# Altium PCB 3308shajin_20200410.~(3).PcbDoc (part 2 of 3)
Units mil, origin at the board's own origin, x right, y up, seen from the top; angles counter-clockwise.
Board outline 4724.41 x 2952.76 mil, 4 copper layers (Top, GND, Power, Bottom), stack 35.4 mil thick; 266 components, 266 nets, 1212 pads, 1516 vias.
Unrouted connection lines stored in the file: 149.

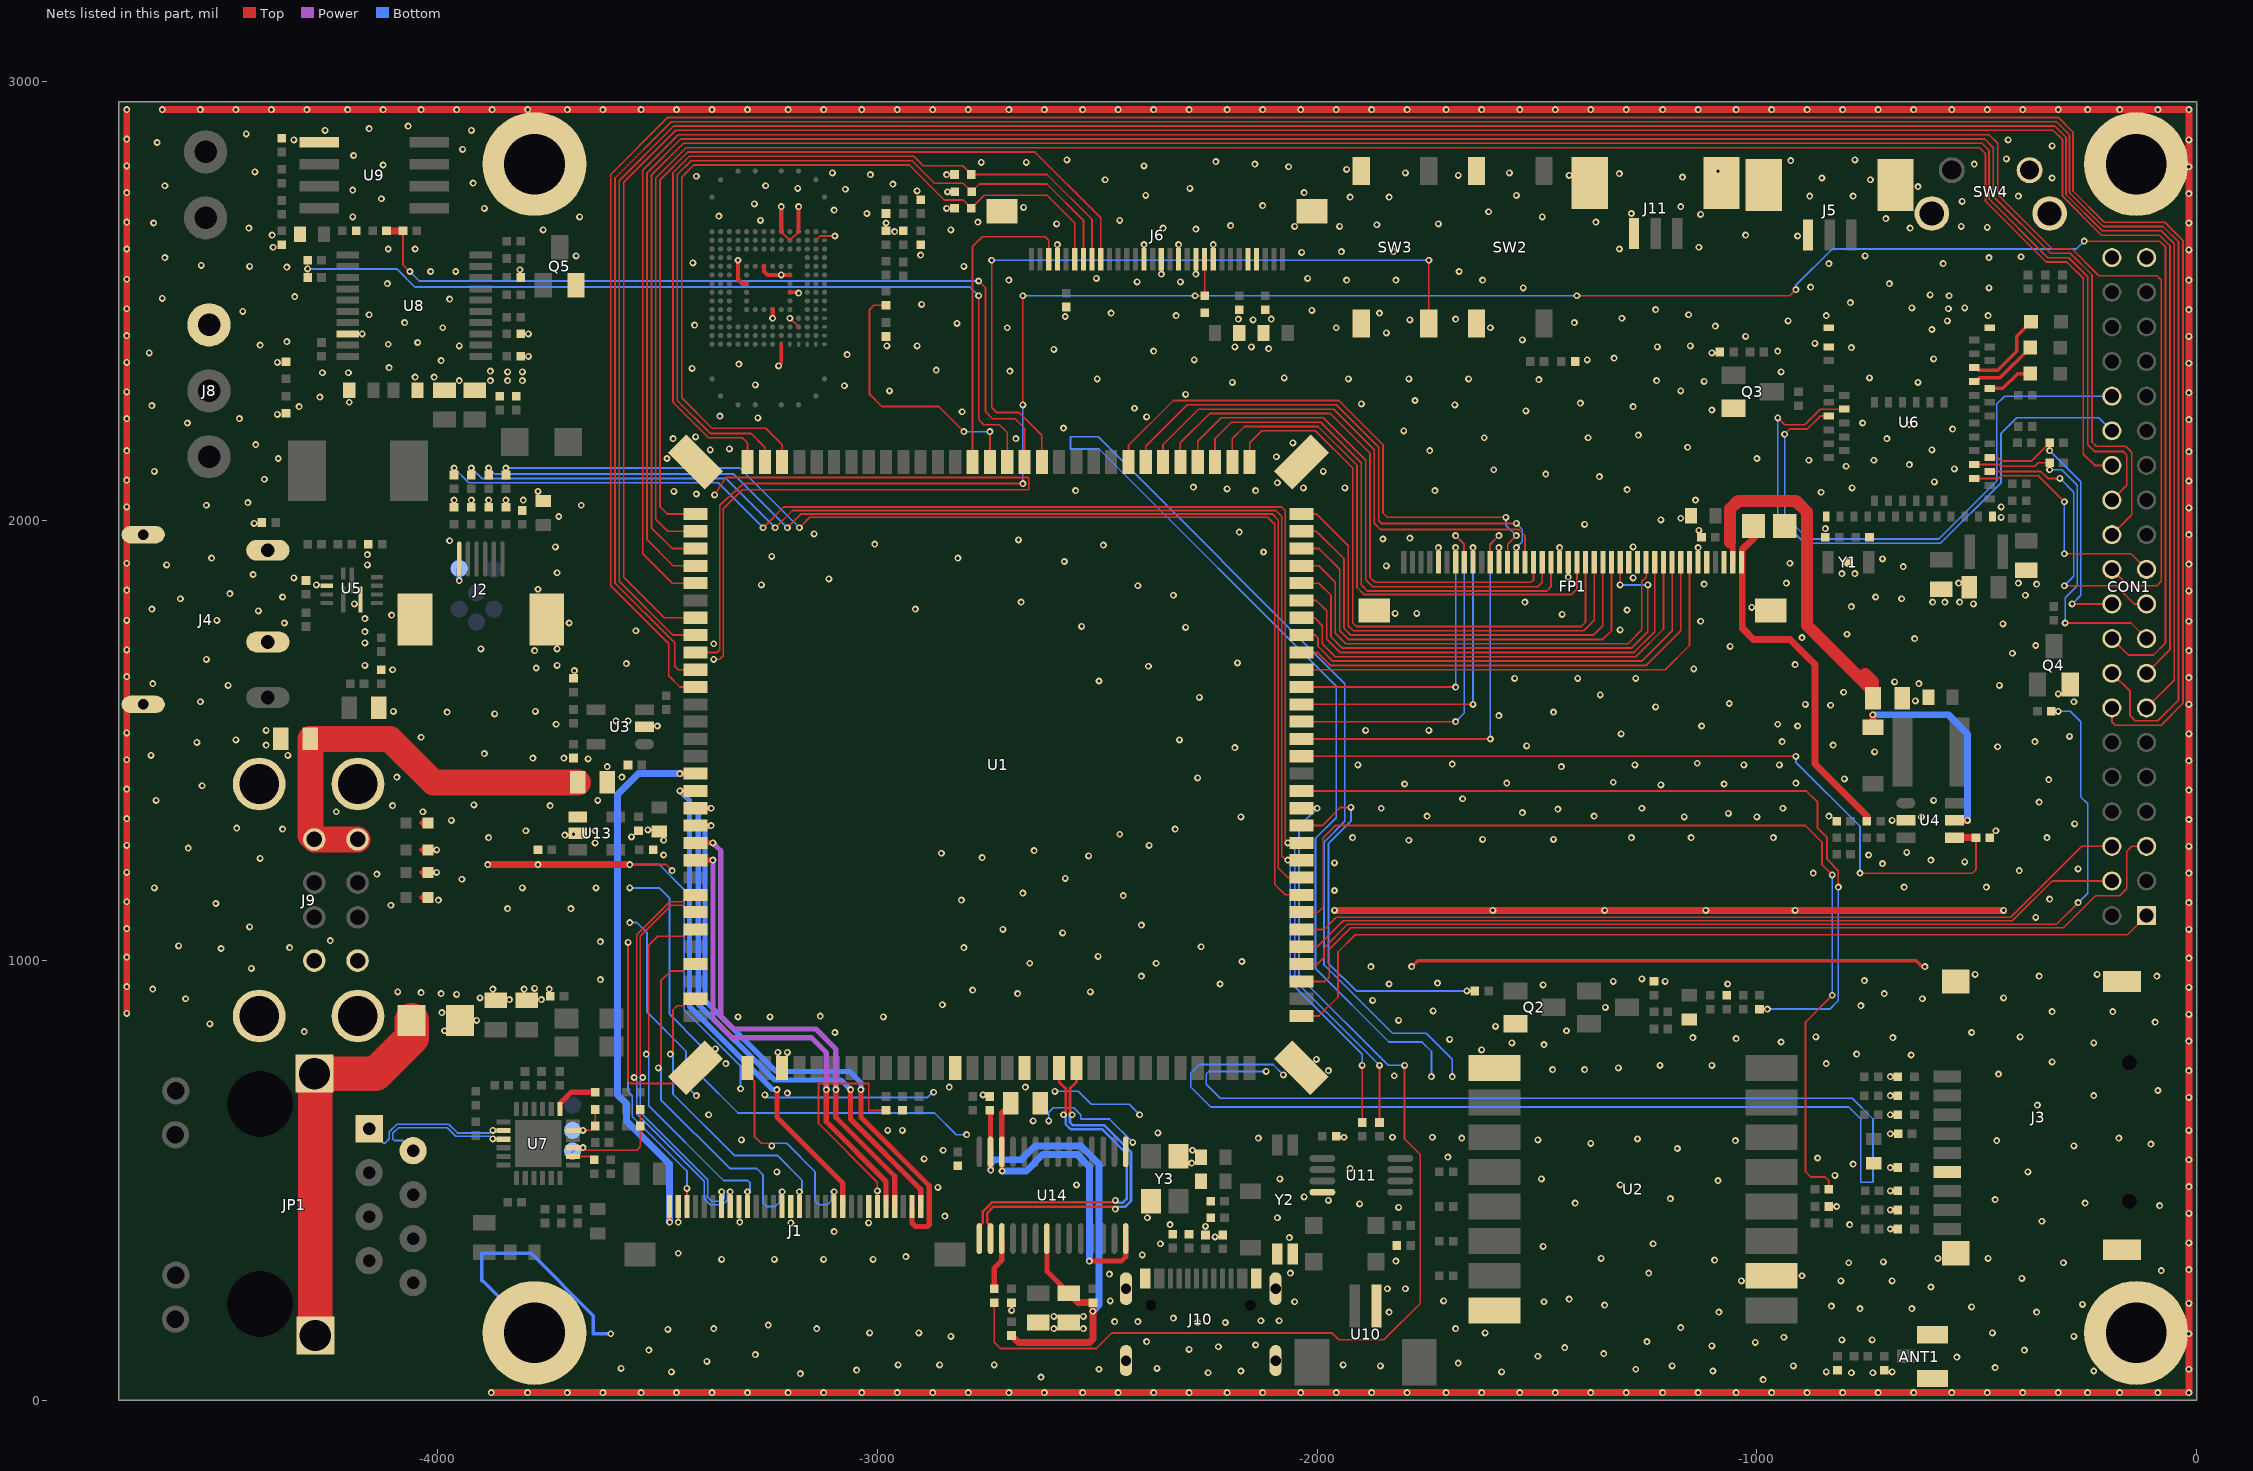
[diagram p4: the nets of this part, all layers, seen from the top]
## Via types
v1: diameter 15.75, hole 7.87, Top to Bottom, 1478 vias
v2: diameter 19.68, hole 11.81, Top to Bottom, 38 vias

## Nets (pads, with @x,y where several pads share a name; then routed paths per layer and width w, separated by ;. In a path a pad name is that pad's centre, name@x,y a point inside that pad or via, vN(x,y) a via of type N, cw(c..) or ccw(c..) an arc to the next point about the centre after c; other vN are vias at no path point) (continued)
FLASH_ALE/EMMC_RST: R77.1 U1.46 | length 612
  Top w3.94: R77.1@-2980.31,2490.16 -3007.87,2490.16 -3017.72,2480.31 -3017.72,2287.4 -2990.16,2259.84 -2860.24,2259.84 v1(-2803.15,2202.76) ; U1.46@-2744.09,2133.86 v1(-2744.09,2202.76)
  Bottom w3.94: v1(-2803.15,2202.76) v1(-2744.09,2202.76)
FLASH_CS0N: R64.2 R66.2 U1.44 | length 1923.3
  Top w3.94: R66.2@-4078.74,2659.45 -4078.74,2582.68 v1(-4062.99,2566.93) ; v1(-2769.69,2545.28) -2753.94,2529.53 -2753.94,2248.03 -2738.19,2232.28 -2687.01,2232.28 -2665.35,2210.63 U1.44@-2665.35,2133.86
  Top w15.75: R64.2@-4116.14,2659.45 R66.2@-4078.74,2659.45
  Bottom w3.94: v1(-4062.99,2566.93) -4041.34,2545.28 v1(-2769.69,2545.28)
FLASH_RDN: J6.28 U1.47 | length 718.9
  Top w3.94: U1.47@-2783.46,2133.86 -2783.46,2624.02 -2761.81,2645.67 -2618.11,2645.67 -2610.24,2637.8 J6.28@-2610.24,2594.49
FLASH_RDY: R63.2 R65.2 U1.45 | length 2015.9
  Top w3.94: R63.2@-4295.28,2553.15 v1(-4295.28,2572.83) R65.2@-4295.28,2592.52 ; v1(-2769.69,2511.81) -2769.69,2230.31 -2757.87,2218.5 -2722.44,2218.5 -2704.72,2200.79 U1.45@-2704.72,2133.86
  Bottom w3.94: v1(-4295.28,2572.83) -4092.52,2572.83 -4051.18,2531.5 -2789.37,2531.5 v1(-2769.69,2511.81)
GBE0_SDP: R81.2 U14.17 | length 121.2
  Top w11.81: R81.2@-2734.25,253.94 -2734.25,301.18 -2717.03,318.4 U14.17@-2717.03,368.03
GND: ANT1.2 ANT1.3 C1.2 C2.2 C3.2 C4.2 C5.2 C7.2 C8.2 C9.2 C10.2 C11.2 C12.2 C13.2 C14.2 C15.1 C16.2 C17.2 C19.2 C20.2 C21.2 C22.2 C23.2 C24.2 C25.2 C26.2 C27.2 C28.2 C29.2 C30.2 C31.2 C32.1 C33.1 C34.1 C49.2 C50.2 C51.2 C52.2 C53.2 C54.2 C55.2 C58.2 C59.2 C60.1 C61.1 C62.1 C63.2 C64.1 C65.2 C66.2 C67.2 C68.2 C69.2 C70.1 C71.1 C72.2 C73.2 C74.2 C75.2 C76.2 C77.1 C78.1 C79.1 C80.1 CD1.1 CD2.1 CD3.1 CON1.39 CON1.40 D2.2 D3.2 D4.2 D5.2 D6.2 D7.2 D8.2 D9.2 D10.2 D11.2 D12.2 D16.2 D17.2 E1.2 E2.2 ED1.2 ED2.1 ED3.2 ED4.1 ED5.2 ED6.2 ED7.2 ED8.2 ED9.2 ED10.2 FP1.3 FP1.5 FP1.6 FP1.13 FP1.14 FP1.21 FP1.22 FP1.29 FP1.36 FP1.41 FP1.42 J1.2 J1.3 J1.9 J1.15 J1.24 J1.25 J2.1 J2.7 J2.8 J3.6 J3.10 J3.11 J3.12 J3.13 J4.2 J4.3 J4.4 J4.5 J5.3 J5.4 J5.5 J6.4 J6.5 J6.9 J6.11 J6.13 J6.15 J6.17 J6.27 J6.31 J6.32 J8.3 J9.4 J9.8 J9.9 J9.10 J9.11 J9.12 J10.A1 J10.A12 J10.B1 J10.B12 J10.E1 J10.E2 J10.E3 J10.E4 J11.3 J11.4 J11.5 P1.1 Q2.2 Q3.2 Q4.2 Q5.2 R3.2 R16.1 R20.2 R30.1 R35.1 R41.2 R57.1 R62.2 R71.2 R73.2 R82.1 R83.1 R84.1 R85.1 R87.1 SW2.1 SW2.4 SW3.1 SW3.4 SW4.1 SW4.3 SW4.4 TP1.1 TP2.1 TP3.1 TP4.1 U1.93 U1.103 U1.107 U1.121 U1.122 U1.123 U1.124 U2.2 U2.9 U2.16 U3.2 U4.2 U5.2 U5.10 U6.1 U6.2 U6.15 U6.33 U6.55 U8.18 U9.5 U10.1 U11.4 U13.2 U14.1 Y1.3 Y2.3 Y2.4 Y3.2 Y3.4 | length 32052.8
  Top w3.94: v1(-3566.93,1041.34) -3566.93,726.38 -3561.02,720.47 -3452.76,720.47 -3416.93,756.3 U1.124@-3413.78,756.3 ; v1(-3562.99,1218.5) -3480.31,1218.5 v1(-3466.54,1204.72) ; J1.3@-3433.07,440.94 v1(-3433.07,482.28) ; v1(-3372.05,1685.04) -3358.27,1685.04 -3350.39,1692.91 -3350.39,2027.56 -3307.09,2070.87 -2655.51,2070.87 -2655.51,2098.43 -3344.49,2098.43 v1(-3370.08,2059.06) ; -3218.5,2657.48 -3198.82,2637.8 -3179.13,2657.48 ; v1(-3198.82,2460.63) -3179.13,2440.94 ; -3139.76,2637.8 -3129.92,2647.64 v1(-3096.46,2647.64) ; v1(-3000,476.38) -3000,496.06 -3133.86,629.92 -3133.86,720.47 -3019.69,720.47 -3019.69,657.48 -3017.72,659.45 R3.2@-2980.31,659.45
  Top w7.87: v1(-3224.41,2352.36) -3218.5,2358.27 -3218.5,2401.57 ; -3198.82,2519.68 -3181.1,2519.68 v1(-3179.13,2517.72) ; v1(-1785.43,986.22) -1771.65,1000 -637.8,1000 -624.02,986.22 v1(-618.11,986.22)
  Top w9.84: v1(-3316.93,2592.52) -3316.93,2549.21 -3307.09,2539.37 -3297.24,2539.37 ; -3257.87,2578.74 -3257.87,2566.93 -3250,2559.06 v1(-3218.5,2559.06) -3198.82,2559.06 ; v1(-3238.19,2460.63) -3238.19,2480.31 ; -3218.5,2657.48 v1(-3218.5,2714.57) ; -3179.13,2657.48 v1(-3179.13,2714.57)
  Top w15.75: v1(-4706.69,879.92) v1(-4706.69,940.94) v1(-4706.69,1007.87) v1(-4706.69,1072.83) v1(-4706.69,1133.86) v1(-4706.69,1200.79) v1(-4706.69,1261.81) v1(-4706.69,1322.83) v1(-4706.69,1389.76) v1(-4706.69,1456.69) v1(-4706.69,1517.72) v1(-4706.69,1645.67) v1(-4706.69,1706.69) v1(-4706.69,1773.62) v1(-4706.69,1842.52) v1(-4706.69,1903.54) v1(-4706.69,2031.5) v1(-4706.69,2092.52) v1(-4706.69,2159.45) v1(-4706.69,2232.28) v1(-4706.69,2293.31) v1(-4706.69,2360.24) v1(-4706.69,2421.26) v1(-4706.69,2482.28) v1(-4706.69,2549.21) v1(-4706.69,2618.11) v1(-4706.69,2679.13) v1(-4706.69,2746.06) v1(-4706.69,2807.09) v1(-4706.69,2868.11) v1(-4706.69,2935.04) ; v1(-4625.98,2935.04) v1(-4539.37,2935.04) v1(-4458.66,2935.04) v1(-4377.95,2935.04) v1(-4297.24,2935.04) v1(-4204.72,2935.04) v1(-4124.02,2935.04) v1(-4037.4,2935.04) v1(-3956.69,2935.04) v1(-3875.98,2935.04) v1(-3795.28,2935.04) v1(-3704.72,2935.04) v1(-3624.02,2935.04) v1(-3537.4,2935.04) v1(-3456.69,2935.04) v1(-3375.98,2935.04) v1(-3295.28,2935.04) v1(-3202.76,2935.04) v1(-3122.05,2935.04) v1(-3035.43,2935.04) v1(-2954.72,2935.04) v1(-2874.02,2935.04) v1(-2793.31,2935.04) v1(-2700.79,2935.04) v1(-2620.08,2935.04) v1(-2533.46,2935.04) v1(-2452.76,2935.04) v1(-2372.05,2935.04) v1(-2291.34,2935.04) v1(-2204.72,2935.04) v1(-2124.02,2935.04) v1(-2037.4,2935.04) v1(-1956.69,2935.04) v1(-1875.98,2935.04) v1(-1795.28,2935.04) v1(-1706.69,2935.04) v1(-1625.98,2935.04) v1(-1539.37,2935.04) v1(-1458.66,2935.04) v1(-1377.95,2935.04) v1(-1297.24,2935.04) v1(-1214.57,2935.04) v1(-1133.86,2935.04) v1(-1047.24,2935.04) v1(-966.54,2935.04) v1(-885.83,2935.04) v1(-805.12,2935.04) v1(-724.41,2935.04) v1(-643.7,2935.04) v1(-557.09,2935.04) v1(-476.38,2935.04) v1(-395.67,2935.04) v1(-314.96,2935.04) v1(-248.03,2935.04) v1(-175.2,2935.04) v1(-88.58,2935.04) v1(-17.72,2935.04) v1(-17.72,2866.14) v1(-17.72,2805.12) v1(-17.72,2744.09) v1(-17.72,2677.17) v1(-17.72,2616.14) v1(-17.72,2547.24) v1(-17.72,2480.31) v1(-17.72,2419.29) v1(-17.72,2358.27) v1(-17.72,2291.34) v1(-17.72,2230.31) v1(-17.72,2157.48) v1(-17.72,2090.55) v1(-17.72,2029.53) v1(-17.72,1968.5) v1(-17.72,1901.57) v1(-17.72,1840.55) v1(-17.72,1771.65) v1(-17.72,1704.72) v1(-17.72,1643.7) v1(-17.72,1582.68) v1(-17.72,1515.75) v1(-17.72,1454.72) v1(-17.72,1387.8) v1(-17.72,1320.87) v1(-17.72,1259.84) v1(-17.72,1198.82) v1(-17.72,1131.89) v1(-17.72,1070.87) v1(-17.72,1005.91) v1(-17.72,938.98) v1(-17.72,877.95) v1(-17.72,816.93) v1(-17.72,750) v1(-17.72,688.98) v1(-17.72,614.17) v1(-17.72,547.24) v1(-17.72,486.22) v1(-17.72,425.2) v1(-17.72,358.27) v1(-17.72,297.24) v1(-17.72,220.47) v1(-17.72,151.57) v1(-17.72,70.87) v1(-17.72,17.72) v1(-88.58,17.72) v1(-175.2,17.72) v1(-248.03,17.72) v1(-314.96,17.72) v1(-395.67,17.72) v1(-476.38,17.72) v1(-557.09,17.72) v1(-643.7,17.72) v1(-724.41,17.72) v1(-805.12,17.72) v1(-885.83,17.72) v1(-966.54,17.72) v1(-1047.24,17.72) v1(-1133.86,17.72) v1(-1214.57,17.72) v1(-1297.24,17.72) v1(-1377.95,17.72) v1(-1458.66,17.72) v1(-1539.37,17.72) v1(-1625.98,17.72) v1(-1706.69,17.72) v1(-1795.28,17.72) v1(-1875.98,17.72) v1(-1956.69,17.72) v1(-2037.4,17.72) v1(-2124.02,17.72) v1(-2204.72,17.72) v1(-2291.34,17.72) v1(-2372.05,17.72) v1(-2452.76,17.72) v1(-2533.46,17.72) v1(-2620.08,17.72) v1(-2700.79,17.72) v1(-2793.31,17.72) v1(-2874.02,17.72) v1(-2954.72,17.72) v1(-3035.43,17.72) v1(-3122.05,17.72) v1(-3202.76,17.72) v1(-3295.28,17.72) v1(-3375.98,17.72) v1(-3456.69,17.72) v1(-3537.4,17.72) v1(-3624.02,17.72) v1(-3704.72,17.72) v1(-3795.28,17.72) v1(-3877.95,17.72) ; v1(-3885.83,1218.5) v1(-3771.65,1218.5) v1(-3562.99,1218.5) ; v1(-1960.63,1114.17) v1(-1600.39,1114.17) v1(-1346.46,1114.17) v1(-1116.14,1114.17) v1(-913.39,1114.17) v1(-438.98,1114.17)
  Bottom w3.94: v1(-3566.93,1041.34) -3566.93,702.76 -3557.09,692.91 -3557.09,645.67 -3433.07,521.65 v1(-3433.07,482.28) ; v1(-3562.99,1086.61) -3547.24,1086.61 -3523.62,1062.99 -3523.62,882.35 -3435.04,793.76 -3435.04,716.54 v1(-3411.42,692.91) ; v1(-3562.99,1165.35) -3496.06,1165.35 -3472.44,1141.73 -3472.44,877.95 -3403.54,809.06 -3403.54,740.16 -3316.93,653.54 -2870.08,653.54 -2820.87,604.33 v1(-2797.24,604.33) ; v1(-3562.99,1218.5) -3496.06,1218.5 -3438.98,1161.42 -3438.98,887.8 -3311.02,759.84 v1(-3311.02,708.66) ; v1(-3255.91,694.88) -3250,688.98 -2885.83,688.98 -2875.98,698.82 -2874.02,698.82 v1(-2872.05,700.79) ; v1(-2610.24,635.83) -2610.24,655.51 -2600.39,665.35 -2553.15,665.35 -2537.4,649.61 -2537.4,639.76 -2472.44,639.76 v1(-2419.29,586.61) ; v1(-2596.46,702.76) -2543.31,702.76 -2513.78,673.23 -2427.17,673.23 v1(-2403.54,649.61) ; v1(-2116.14,748.03) -2246.06,748.03 -2251.97,742.13 -2251.97,718.5 -2220.47,687.01 -783.46,687.01 -736.22,639.76 -736.22,496.06 -763.78,496.06 -763.78,639.76 -791.34,667.32 -2242.13,667.32 -2287.4,712.6 -2287.4,744.09 -2267.72,763.78 -2100.39,763.78 v1(-2076.77,740.16) ; v1(-1740.16,736.22) -1740.16,793.31 -1761.81,814.96 -1836.61,814.96 -2003.94,982.28 -2003.94,1277.56 -1956.69,1324.8 -1956.69,1624.02 -2496.06,2163.39 -2561.02,2163.39 -2561.02,2190.94 -2498.03,2190.94 -1937.01,1629.92 -1937.01,1316.93 -1984.25,1269.68 -1984.25,990.16 -1828.74,834.65 -1751.97,834.65 -1692.91,775.59 v1(-1692.91,736.22)
  Bottom w7.87: TP1.1@-3779.53,153.54 -3897.64,271.65 -3899.61,271.65 -3899.61,334.65 -3787.4,334.65 -3645.67,192.91 -3645.67,151.57 v1(-3606.3,151.57)
  Bottom w11.81: v1(-3950.79,1864.17) P1.1@-3950.79,1891.73
  other v1: -986.22,47.24 -2627.95,53.15 -3175.2,61.02 -2248.03,62.99 -785.43,62.99 -736.22,62.99 -3468.5,64.96 -1580.71,64.96 -842.52,64.96 -692.91,64.96 -2173.23,66.93 -1100.39,66.93 -234.25,66.93 -3047.24,68.9 -2496.06,70.87 -1275.59,70.87 -3582.68,72.83 -2364.17,72.83 -458.66,74.8 -1856.3,78.74 -1192.91,78.74 -917.32,78.74 -2952.76,80.71 -2858.27,80.71 -2734.25,80.71 -1940.94,80.71 -1679.13,84.65 -3387.8,88.58 -545.28,98.43 -1498.03,100.39 -3277.56,104.33 -1348.43,106.3 -3519.69,114.17 -391.73,114.17 -2291.34,116.14 -1437.01,120.08 -2224.41,122.05 -1102.36,124.02 -2139.76,125.98 -1003.94,131.89 -2387.8,133.86 -1250,133.86 -807.09,137.8 -738.19,137.8 -938.98,143.7 -2832.68,145.67 -279.53,145.67 -3017.72,153.54 -2905.51,153.54 -1618.11,153.54 -464.57,153.54 -3476.38,161.42 -3372.05,163.39 -3137.8,163.39 -2598.43,163.39 -2531.5,163.39 -1685.04,163.39 -1173.23,165.35 -3248.03,171.26 -2271.65,177.17 -2208.66,177.17 -2460.63,179.13 -2407.48,179.13 -2127.95,181.1 -2086.61,181.1 -2326.77,187.01 -2598.43,190.94 -2531.5,190.94 -1836.61,200.79 -1086.61,200.79 -364.17,200.79 -2694.88,204.72 -765.75,208.66 -647.64,208.66 -511.81,212.6 -830.71,214.57 -1346.46,216.54 -259.84,218.5 -2051.18,224.41 -1484.25,224.41 -2470.47,226.38 -1712.6,226.38 -1427.17,230.31 -1840.55,253.94 -1799.21,253.94 -604.33,257.87 -1035.43,271.65 -809.06,271.65 -692.91,271.65 -397.64,277.56 -897.64,283.46 -2472.44,287.4 -2061.02,289.37 -1246.06,289.37 -80.71,295.28 -791.34,312.99 -303.15,312.99 -712.6,314.96 -1820.87,316.93 -1096.46,318.9 -3354.33,320.87 -3234.25,320.87 -3122.05,320.87 -3009.84,320.87 -1354.33,322.83 -588.58,322.83 -474.41,322.83 -2935.04,326.77 -2397.64,330.71 -3452.76,334.65 -1486.22,350.39 -2356.3,356.3 -1236.22,356.3 -2062.99,370.08 -2232.28,372.05 -3098.43,383.86 -696.85,389.76 -2253.94,395.67 -2334.65,399.61 -789.37,399.61 -3196.85,403.54 -3019.69,403.54 -3452.76,405.51 -3312.99,405.51 -352.36,407.48 -2385.83,415.35 -2090.55,415.35 -2846.46,419.29 -696.85,433.07 -1814.96,438.98 -818.9,440.94 -84.65,442.91 -1903.54,446.85 -1413.39,448.82 -253.94,448.82 -1974.41,454.72 -458.66,456.69 -1196.85,458.66 -2029.53,462.6 -696.85,476.38 -2862.2,484.25 -2547.24,490.16 -1311.02,490.16 -1088.58,500 -2084.65,503.94 -1490.16,503.94 -822.83,511.81 -3228.35,519.68 -383.86,519.68 -1925.2,527.56 -696.85,529.53 -781.5,537.4 -2285.43,539.37 -2893.7,549.21 -862.2,551.18 -1702.76,553.15 -2850.39,568.9 -2283.46,568.9 -1181.1,572.83 -279.53,578.74 -104.33,582.68 -1377.95,584.65 -1049.21,590.55 -454.72,590.55 -3309.06,592.52 -1498.03,592.52 -1271.65,594.49 -2133.86,596.46 -1671.26,596.46 -177.17,596.46 -1938.98,598.43 -1828.74,598.43 -1738.19,598.43 -696.85,606.3 -2362.2,608.27 -2976.38,614.17 -2942.91,614.17 -2645.67,635.83 -3383.86,649.61 -696.85,649.61 -362.2,671.26 -696.85,692.91 -234.25,692.91 -2759.84,694.88 -3204.72,698.82 -88.58,704.72 -2836.61,712.6 -2663.39,712.6 -696.85,736.22 -1824.8,738.19 -450.79,742.13 -1974.41,750 -1464.57,751.97 -1391.73,751.97 -1314.96,755.91 -1220.47,761.81 -1102.36,761.81 -3344.49,765.75 -842.52,765.75 -328.74,769.68 -2001.97,775.59 -649.61,785.43 -773.62,787.4 -3226.38,791.34 -3204.72,791.34 -1625.98,797.24 -3368.11,799.21 -1484.25,809.06 -1557.09,812.99 -234.25,812.99 -944.88,814.96 -1698.82,820.87 -1047.24,822.83 -1145.67,824.8 -690.94,824.8 -866.14,826.77 -401.57,826.77 -3096.46,836.61 -511.81,836.61 -4303.15,838.58 -3984.25,840.55 -1433.07,840.55 -1594.49,850.39 -4517.72,856.3 -94.49,860.24 -3911.42,864.17 -1814.96,864.17 -3316.93,872.05 -3244.09,872.05 -2986.22,872.05 -3129.92,874.02 -3990.16,881.89 -328.74,883.86 -190.94,883.86 -1736.22,885.83 -1344.49,893.7 -763.78,897.64 -2852.36,899.61 -1874.02,909.45 -3836.61,911.42 -3763.78,911.42 -4572.83,913.39 -624.02,913.39 -3903.54,915.35 -438.98,915.35 -3956.69,923.23 -3992.13,925.2 -2681.1,925.2 -710.63,925.2 -4037.4,927.17 -4090.55,929.13 -2515.75,929.13 -2783.46,933.07 -4647.64,935.04 -3874.02,935.04 -3803.15,935.04 -3746.06,935.04 -3779.53,937.01 -1486.22,944.88 -2220.47,946.85 -1836.61,946.85 -1066.93,946.85 -1726.38,948.82 -1326.77,952.76 -1208.66,952.76 -755.91,954.72 -3629.92,956.69 -1261.81,958.66 -2399.61,964.57 -358.27,964.57 -90.55,964.57 -503.94,968.5 -226.38,968.5 -4423.23,982.28 -1877.95,986.22 -2653.54,994.09 -2366.14,994.09 -2171.26,998.03 -2498.03,1009.84 -4492.13,1027.56 -4336.61,1029.53 -2803.15,1029.53 -2263.78,1031.5 -4588.58,1033.46 -3629.92,1043.31 -4244.09,1045.28 -2578.74,1062.99 -2714.57,1070.87 -4427.17,1076.77 -2399.61,1080.71 -366.14,1098.43 -3840.55,1118.11 -3696.85,1118.11 -4106.3,1125.98 -4503.94,1129.92 -3998.03,1137.8 -2809.06,1137.8 -334.65,1139.76 -2440.94,1147.64 -2669.29,1153.54 -1960.63,1159.45 -4643.7,1165.35 -3807.09,1165.35 -3639.76,1165.35 -665.35,1167.32 -478.35,1167.32 -3944.88,1185.04 -2572.83,1187.01 -4137.8,1196.85 -872.05,1198.82 -4001.97,1200.79 -403.54,1204.72 -269.69,1208.66 -714.57,1220.47 -1960.63,1222.44 -527.56,1224.41 -604.33,1228.35 -4403.54,1232.28 -2761.81,1234.25 -2519.69,1238.19 -3486.22,1240.16 -746.06,1240.16 -2854.33,1244.09 -659.45,1246.06 -2643.7,1250 -4001.97,1251.97 -4566.93,1255.91 -2381.89,1261.81 -3641.73,1267.72 -3486.22,1273.62 -1791.34,1273.62 -1624.02,1275.59 -1462.6,1275.59 -3883.86,1279.53 -1919.29,1279.53 -1285.43,1279.53 -1149.61,1279.53 -962.6,1279.53 -340.55,1279.53 -3559.06,1281.5 -3710.63,1285.43 -3690.94,1287.4 -2448.82,1287.4 -3799.21,1295.28 -3641.73,1295.28 -456.69,1295.28 -3521.65,1297.24 -4352.36,1299.21 -2322.83,1299.21 -4456.69,1301.18 -277.56,1311.02 -3968.5,1318.9 -692.91,1318.9 -2173.23,1326.77 -1165.35,1326.77 -1000,1326.77 -625.98,1326.77 -1750,1328.74 -1370.08,1328.74 -836.61,1328.74 -1064.96,1334.65 -1533.46,1336.61 -4230.31,1338.58 -4033.46,1338.58 -1452.76,1344.49 -1854.33,1346.46 -1261.81,1346.46 -940.94,1346.46 -4102.36,1352.36 -3744.09,1352.36 -3917.32,1354.33 -358.27,1360.24 -4639.76,1364.17 -3635.83,1364.17 -598.43,1364.17 -1669.29,1368.11 -4535.43,1397.64 -1218.5,1399.61 -1801.18,1401.57 -1074.8,1401.57 -1568.9,1403.54 -911.42,1403.54 -1326.77,1405.51 -336.61,1411.42 -801.18,1413.39 -2271.65,1415.35 -4092.52,1417.32 -3580.71,1417.32 -3614.17,1440.94 -1444.88,1440.94 -1907.48,1444.88 -1277.56,1444.88 -1029.53,1444.88 -948.82,1444.88 -1692.91,1446.85 -1135.83,1448.82 -3657.48,1458.66 -3783.46,1460.63 -3712.6,1460.63 -4651.57,1466.54 -4340.55,1466.54 -3893.7,1470.47 -732.28,1474.41 -2187.01,1484.25 -452.76,1486.22 -1523.62,1488.19 -4389.76,1490.16 -826.77,1490.16 -4547.24,1496.06 -942.91,1498.03 -368.11,1498.03 -4458.66,1501.97 -2312.99,1501.97 -4037.4,1507.87 -289.37,1509.84 -1309.06,1515.75 -4389.76,1523.62 -1889.76,1523.62 -1746.06,1523.62 -3500,1533.46 -1125.98,1533.46 -907.48,1533.46 -3730.31,1537.4 -952.76,1537.4 -3594.49,1545.28 -3566.93,1545.28 -1586.61,1557.09 -3870.08,1561.02 -3978.35,1564.96 -1462.6,1564.96 -4100.39,1566.93 -3777.56,1566.93 -1230.31,1576.77 -832.68,1580.71 -889.76,1582.68 -1062.99,1584.65 -4539.37,1588.58 -279.53,1588.58 -639.76,1590.55 -2267.72,1598.43 -1356.3,1604.33 -314.96,1606.3 -803.15,1610.24 -4476.38,1625.98 -448.82,1625.98 -4647.64,1629.92 -631.89,1629.92 -687.01,1633.86 -2496.06,1635.83 -1551.18,1641.73 -1407.48,1641.73 -1275.59,1641.73 -3688.98,1659.45 -4102.36,1661.42 -1143.7,1663.39 -3775.59,1665.35 -2383.86,1669.29 -4165.35,1671.26 -3728.35,1671.26 -913.39,1673.23 -3570.87,1675.2 -2181.1,1677.17 -4525.59,1685.04 -419.29,1698.82 -3779.53,1704.72 -3901.57,1708.66 -3728.35,1708.66 -1061.02,1714.57 -366.14,1716.54 -3372.05,1720.47 -4165.35,1722.44 -641.73,1732.28 -897.64,1734.25 -795.28,1742.13 -4165.35,1748.03 -3549.21,1750 -1311.02,1751.97 -2299.21,1757.87 -2535.43,1759.84 -440.94,1765.75 -4348.43,1767.72 -3700.79,1767.72 -1127.95,1771.65 -4501.97,1773.62 -4165.35,1777.56 -4104.33,1785.43 -1442.91,1787.4 -1822.83,1789.37 -1773.62,1789.37 -4407.48,1795.28 -1295.28,1797.24 -4649.61,1799.21 -2913.39,1799.21 -1011.81,1803.15 -785.43,1805.12 -4188.98,1811.02 -507.87,1811.02 -2673.23,1814.96 -1527.56,1814.96 -600.39,1814.96 -572.83,1814.96 -539.37,1814.96 -4584.65,1822.83 -671.26,1822.83 -4352.36,1826.77 -730.31,1826.77 -2326.77,1830.71 -389.76,1830.71 -4472.44,1834.65 -3771.65,1844.49 -2407.48,1852.36 -4275.59,1854.33 -3263.78,1854.33 -1120.08,1856.3 -364.17,1856.3 -933.07,1858.27 -541.34,1858.27 -405.51,1858.27 -3110.24,1868.11 -4326.77,1870.08 -1281.5,1870.08 -1429.13,1872.05 -4419.29,1877.95 -807.09,1879.92 -777.56,1879.92 -3728.35,1881.89 -667.32,1895.67 -1842.52,1897.64 -4616.14,1899.61 -4159.45,1899.61 -925.2,1903.54 -2574.8,1907.48 -714.57,1913.39 -4513.78,1915.35 -2816.93,1915.35 -3240.16,1919.29 -4159.45,1923.23 -2122.05,1929.13 -1724.41,1938.98 -1586.61,1938.98 -1448.82,1938.98 -1133.86,1938.98 -3732.28,1940.94 -1281.5,1940.94 -2486.22,1944.88 -3005.91,1946.85 -3972.44,1954.72 -2679.13,1956.69 -1850.39,1958.66 -1789.37,1960.63 -3143.7,1970.47 -2177.17,1974.41 -1131.89,1978.35 -844.49,1982.28 -1391.73,1992.13 -4417.32,1994.09 -1218.5,2001.97 -1173.23,2005.91 -444.88,2007.87 -3724.41,2009.84 -444.88,2031.5 -4525.59,2035.43 -3673.23,2035.43 -4431.1,2041.34 -3962.6,2047.24 -3923.23,2047.24 -3883.86,2047.24 -3844.49,2047.24 -3805.12,2047.24 -1139.76,2047.24 -3411.42,2061.02 -854.33,2064.96 -3771.65,2066.93 -3462.6,2066.93 -2549.21,2068.9 -2139.76,2068.9 -1732.28,2068.9 -1295.28,2070.87 -2204.72,2072.83 -2031.5,2074.8 -1937.01,2074.8 -783.46,2074.8 -2281.5,2076.77 -2090.55,2086.61 -596.46,2088.58 -4393.7,2094.49 -1358.27,2100.39 -1480.31,2106.3 -4643.7,2112.2 -1986.22,2112.2 -1598.43,2116.14 -551.18,2118.11 -797.24,2124.02 -653.54,2127.95 -881.89,2137.8 -734.25,2137.8 -4362.2,2141.73 -3478.35,2141.73 -1000,2141.73 -2092.52,2145.67 -1744.09,2159.45 -3379.92,2161.42 -602.36,2161.42 -3336.61,2163.39 -1157.48,2167.32 -4413.39,2173.23 -2055.12,2177.17 -3464.57,2187.01 -2685.04,2187.01 -704.72,2187.01 -1620.08,2188.98 -1383.86,2188.98 -3413.39,2190.94 -1269.69,2194.88 -1803.15,2204.72 -555.12,2208.66 -2576.77,2210.63 -653.54,2218.5 -4568.9,2222.44 -759.84,2222.44 -4450.79,2232.28 -3271.65,2234.25 -2387.8,2236.22 -3358.27,2238.19 -4364.17,2242.13 -2807.09,2248.03 -1525.59,2250 -1102.36,2251.97 -2415.35,2255.91 -4314.96,2259.84 -1281.5,2259.84 -4649.61,2261.81 -1687.01,2263.78 -1899.61,2265.75 -1401.57,2267.72 -4200.79,2269.68 -1777.56,2273.62 -4267.72,2281.5 -2299.21,2287.4 -2972.44,2295.28 -1173.23,2295.28 -3074.8,2307.09 -3277.56,2309.06 -2192.91,2314.96 -633.86,2314.96 -1120.08,2316.93 -3950.79,2318.9 -3879.92,2318.9 -3840.55,2318.9 -3807.09,2318.9 -1228.35,2318.9 -1496.06,2320.87 -2500,2322.83 -1929.13,2322.83 -1791.34,2322.83 -1655.51,2322.83 -2074.8,2324.8 -744.09,2324.8 -4051.18,2326.77 -4007.87,2326.77 -4261.81,2336.61 -4202.76,2336.61 -3840.55,2338.58 -3807.09,2338.58 -944.88,2338.58 -3879.92,2340.55 -2698.82,2340.55 -2866.14,2342.52 -3421.26,2346.46 -4110.24,2348.43 -3314.96,2356.3 -4364.17,2360.24 -3992.13,2364.17 -2279.53,2366.14 -1385.83,2366.14 -598.43,2368.11 -1324.8,2370.08 -3793.31,2374.02 -3068.9,2377.95 -4655.51,2381.89 -1102.36,2381.89 -2372.05,2385.83 -952.76,2385.83 -2598.43,2389.76 -2110.24,2391.73 -785.43,2393.7 -2187.01,2395.67 -2149.61,2395.67 -1226.38,2395.67 -3950.79,2397.64 -2978.35,2397.64 -2909.45,2397.64 -1151.57,2397.64 -4403.54,2399.61 -4112.2,2401.57 -868.11,2403.54 -4045.28,2405.51 -4342.52,2407.48 -1533.46,2411.42 -1025.59,2419.29 -4171.26,2425.2 -3793.31,2425.2 -1842.52,2427.17 -602.36,2435.04 -3988.19,2438.98 -2704.72,2438.98 -1956.69,2438.98 -1606.3,2438.98 -1094.49,2442.91 -3415.35,2444.88 -2818.9,2448.82 -4074.8,2450.79 -1415.35,2450.79 -929.13,2454.72 -566.93,2454.72 -2145.67,2456.69 -1789.37,2456.69 -2179.13,2458.66 -2104.33,2458.66 -1685.04,2458.66 -1307.09,2460.63 -2572.83,2464.57 -2320.87,2466.54 -842.52,2466.54 -474.41,2466.54 -4155.51,2468.5 -1155.51,2468.5 -2468.5,2472.44 -1858.27,2472.44 -4442.91,2476.38 -2011.81,2478.35 -1230.31,2480.31 -564.96,2482.28 -647.64,2484.25 -527.56,2484.25 -2899.61,2492.13 -787.4,2496.06 -3972.44,2503.94 -4625.98,2505.91 -4324.8,2509.84 -562.99,2511.81 -606.3,2513.78 -1531.5,2529.53 -472.44,2529.53 -877.95,2531.5 -4114.17,2539.37 -698.82,2539.37 -2409.45,2543.31 -2311.02,2543.31 -2700.79,2547.24 -1933.07,2547.24 -1820.87,2547.24 -1624.02,2547.24 -2501.97,2551.18 -2021.65,2551.18 -2354.33,2561.02 -2275.59,2561.02 -4015.75,2566.93 -3958.66,2566.93 -1677.17,2566.93 -3812.99,2570.87 -4342.52,2576.77 -4427.17,2578.74 -2803.15,2578.74 -4537.4,2580.71 -836.61,2584.65 -576.77,2584.65 -3419.29,2586.61 -4620.08,2598.43 -472.44,2598.43 -399.61,2600.39 -3685.04,2602.36 -753.94,2602.36 -2901.57,2604.33 -2035.43,2610.24 -1944.88,2612.2 -1826.77,2612.2 -4112.2,2618.11 -4051.18,2618.11 -1312.99,2618.11 -4374.02,2622.05 -1131.89,2622.05 -2590.55,2627.95 -2393.7,2627.95 -2314.96,2627.95 -2236.22,2627.95 -907.48,2647.64 -4375.98,2649.61 -1025.59,2649.61 -2960.63,2657.48 -3759.84,2661.42 -2832.68,2661.42 -2275.59,2663.39 -4429.13,2665.35 -2350.39,2665.35 -651.57,2665.35 -476.38,2667.32 -2051.18,2669.29 -1948.82,2669.29 -535.43,2669.29 -2196.85,2671.26 -1864.17,2673.23 -2592.52,2675.2 -1724.41,2675.2 -4645.67,2677.17 -2980.31,2677.17 -2771.65,2679.13 -1366.14,2679.13 -3265.75,2683.07 -2448.82,2683.07 -706.69,2687.01 -4192.91,2690.94 -3677.17,2690.94 -1488.19,2690.94 -3360.24,2692.91 -1127.95,2696.85 -3023.62,2698.82 -1285.43,2698.82 -1610.24,2702.76 -3098.43,2706.69 -3893.7,2710.63 -2842.52,2710.63 -2667.32,2712.6 -1173.23,2714.57 -2124.02,2716.54 -3279.53,2720.47 -533.46,2726.38 -4127.95,2732.28 -1925.2,2736.22 -1836.61,2736.22 -879.92,2738.19 -781.5,2738.19 -405.51,2738.19 -2389.76,2740.16 -1547.24,2740.16 -2029.53,2746.06 -2840.55,2748.03 -2909.45,2750 -4192.91,2751.97 -3072.83,2753.94 -3181.1,2755.91 -2289.37,2755.91 -633.86,2759.84 -4620.08,2761.81 -3253.94,2761.81 -2964.57,2765.75 -3919.29,2767.72 -2482.28,2775.59 -742.13,2775.59 -852.36,2779.53 -328.74,2779.53 -1169.29,2781.5 -3411.42,2783.46 -1679.13,2785.43 -1427.17,2785.43 -3015.75,2787.4 -2842.52,2787.4 -1312.99,2789.37 -3102.36,2791.34 -1799.21,2791.34 -1562.99,2791.34 -4415.35,2793.31 -1088.58,2795.28 -1933.07,2799.21 -2064.96,2805.12 -2393.7,2807.09 -4124.02,2809.06 -2141.73,2811.02 -505.91,2811.02 -2763.78,2814.96 -2661.42,2814.96 -2230.31,2816.93 -923.23,2818.9 -2568.9,2820.87 -777.56,2820.87 -433.07,2822.83 -4190.94,2830.71 -3942.91,2844.49 -328.74,2852.36 -4637.8,2860.24 -4326.77,2866.14 -429.13,2866.14 -4435.04,2879.92 -4255.91,2887.8 -3923.23,2887.8 -4155.51,2891.73 -4066.93,2897.64
GND_EARTH: C34.2 JP1.13 JP1.14 | length 890.1
  Top w78.74: JP1.13@-4278.02,147.94 -4278.02,740.94 JP1.14@-4280.02,742.94 -4140.91,742.94 -4059.06,824.8 C34.2@-4059.06,864.17
GPIO: R59.1 U7.14 | length 51.8
  Top w3.94: U7.14@-3692.43,554.63 -3651.09,554.63 R59.1@-3643.7,547.24
GPIO0_A1: CON1.5 U1.3 | length 2134.9
  Top w3.94: U1.3@-2035.43,952.76 -1982.28,952.76 -1972.44,962.6 -1972.44,1025.59 -1923.23,1074.8 -303.15,1074.8 -230.31,1147.64 -175.2,1147.64 -159.45,1163.39 -159.45,1248.03 -147.64,1259.84 CON1.5@-114.17,1259.84
GPIO0_A5: R48.2 U1.4 | length 2339.9
  Top w3.94: U1.4@-2035.43,992.13 -2000,992.13 -1984.25,1007.87 -1984.25,1029.53 -1931.1,1082.68 -318.9,1082.68 v1(-269.69,1131.89) ; R48.2@-330.71,1566.93 v1(-314.96,1566.93)
  Bottom w3.94: v1(-314.96,1566.93) -287.4,1566.93 -263.78,1543.31 -263.78,1372.05 -248.03,1356.3 -248.03,1153.54 v1(-269.69,1131.89)
GPIO0_A6: CON1.4 U1.5 | length 1904.5
  Top w3.94: U1.5@-2035.43,1031.5 -2000,1031.5 -1940.94,1090.55 -419.29,1090.55 -328.74,1181.1 CON1.4@-192.91,1181.1
GPIO0_A7: CON1.6 U1.6 | length 1920.8
  Top w3.94: U1.6@-2035.43,1070.87 -1984.25,1070.87 -1956.69,1098.43 -423.13,1098.43 -261.72,1259.84 CON1.6@-192.91,1259.84
GPIO0_B0: RD2.2 U1.7 | length 2238.4
  Top w3.94: U1.7@-2035.43,1110.24 -1998.03,1110.24 -1986.22,1122.05 -1986.22,1279.53 -1958.66,1307.09 -889.76,1307.09 -852.36,1269.68 -852.36,1218.5 v1(-828.74,1194.88) ; RD2.2@-836.61,480.31 -836.61,500 -844.49,507.87 -877.95,507.87 -889.76,519.68 -889.76,860.24 v1(-828.74,921.26)
  Bottom w3.94: v1(-828.74,921.26) v1(-828.74,1194.88)
GPIO0_B1: R14.1 U1.8 | length 2726.1
  Top w3.94: R14.1@-3844.49,2104.33 v1(-3844.49,2120.08) ; v1(-3177.17,1984.25) -3153.54,2007.87 -2112.2,2007.87 -2096.46,1992.13 -2096.46,1173.23 -2072.83,1149.61 U1.8@-2035.43,1149.61
  Bottom w3.94: v1(-3844.49,2120.08) -3312.99,2120.08 v1(-3177.17,1984.25)
GPIO0_B2: R12.1 U1.9 | length 2739.5
  Top w3.94: R12.1@-3883.86,2104.33 v1(-3883.86,2120.08) ; v1(-3204.72,1984.25) -3173.23,2015.75 -2102.36,2015.75 -2088.58,2001.97 -2088.58,1210.63 -2066.93,1188.98 U1.9@-2035.43,1188.98
  Bottom w3.94: v1(-3883.86,2120.08) -3870.08,2106.3 -3326.77,2106.3 v1(-3204.72,1984.25)
GPIO0_B6: R6.2 U1.12 | length 863.6
  Top w3.94: U1.12@-2035.43,1307.09 -1988.19,1307.09 -1946.85,1348.43 v1(-1923.23,1348.43) ; v1(-1659.45,931.1) R6.2@-1641.73,931.1
  Bottom w3.94: v1(-1923.23,1348.43) -1923.23,1316.93 -1974.41,1265.75 -1974.41,994.09 -1911.42,931.1 v1(-1659.45,931.1)
GPIO0_B7/PWM2/I2C3_SDA: R81.1 U1.13 | length 2434.8
  Top w3.94: R81.1@-2734.25,222.44 -2734.25,131.89 -2720.47,118.11 -2501.97,118.11 -2466.54,153.54 -1966.54,153.54 -1950.79,137.8 -1848.43,137.8 -1765.75,220.47 -1765.75,559.06 -1801.18,594.49 v1(-1801.18,761.81) ; U1.13@-2035.43,1346.46 v1(-2000,1346.46)
  Bottom w3.94: v1(-2000,1346.46) -2041.34,1305.12 -2041.34,964.57 -1838.58,761.81 v1(-1801.18,761.81)
GPIO0_C2: R16.2 U1.16 U4.4 | length 1839.2
  Top w3.94: U1.16@-2035.43,1464.57 v1(-911.42,1464.57) ; v1(-765.75,1198.82) -509.84,1198.82 -501.97,1206.69 R16.2@-501.97,1279.53
  Top w15.75: U4.4@-551.18,1279.53 R16.2@-501.97,1279.53
  Bottom w3.94: v1(-911.42,1464.57) -911.42,1450.79 -765.75,1305.12 v1(-765.75,1198.82)
GPIO0_C4: R8.2 U1.14 | length 1841.5
  Top w3.94: U1.14@-2035.43,1385.83 -887.8,1385.83 -862.2,1360.24 -862.2,1301.18 -840.55,1279.53 -840.55,1230.31 -814.96,1204.72 v1(-814.96,1167.32) ; R8.2@-994.09,889.76 v1(-976.38,889.76)
  Bottom w3.94: v1(-976.38,889.76) -834.65,889.76 -814.96,909.45 v1(-814.96,1167.32)
GPIO1: CON1.30 U6.7 | length 1378.5
  Top w3.94: v1(-952.76,2234.25) -937.01,2218.5 -891.73,2218.5 -856.3,2253.94 U6.7@-801.18,2253.94
  Bottom w3.94: v1(-952.76,2234.25) -952.76,2009.84 -891.73,1948.82 -582.68,1948.82 -444.88,2086.61 -444.88,2198.82 -409.45,2234.25 -222.44,2234.25 CON1.30@-192.91,2204.72
GPIO2: CON1.32 U6.8 | length 1305.8
  Top w3.94: v1(-937.01,2196.85) -925.2,2208.66 -885.83,2208.66 -856.3,2238.19 U6.8@-836.61,2238.19
  Bottom w3.94: v1(-937.01,2196.85) -937.01,2011.81 -883.86,1958.66 -586.61,1958.66 -454.72,2090.55 -454.72,2265.75 -437.01,2283.46 -320.87,2283.46 CON1.32@-192.91,2283.46
GPIO2_A5/I2S0_SCLK_TX: CON1.16 U1.70 | length 6305.3
  Top w3.94: U1.70@-3413.39,1661.42 -3452.76,1661.42 -3460.63,1669.29 -3460.63,1722.44 -3596.46,1858.27 -3596.46,2779.53 -3468.5,2907.48 -318.9,2907.48 -289.37,2877.95 -289.37,2746.06 -212.6,2669.29 -76.77,2669.29 -41.34,2633.86 -41.34,1592.52 -88.58,1545.28 -139.76,1545.28 -151.58,1557.09 -151.58,1612.2 CON1.16@-192.91,1653.54
GPIO2_B1/I2S0_SDO0: CON1.22 U1.65 | length 5527.9
  Top w3.94: U1.65@-3413.39,1858.27 -3466.54,1858.27 -3533.46,1925.2 -3533.46,2797.24 -3452.76,2877.95 -472.44,2877.95 -452.76,2858.27 -452.76,2742.13 -328.74,2618.11 -283.46,2618.11 -222.44,2557.09 -90.55,2557.09 -80.71,2547.24 -80.71,1862.2 -90.55,1852.36 -155.51,1852.36 CON1.22@-192.91,1889.76
GPIO2_B2/I2S0_SDO1: CON1.24 U1.64 | length 5165.2
  Top w3.94: U1.64@-3413.39,1897.64 -3464.57,1897.64 -3523.62,1956.69 -3523.62,2791.34 -3446.85,2868.11 -482.28,2868.11 -462.6,2848.43 -462.6,2738.19 -332.68,2608.27 -287.4,2608.27 -238.19,2559.06 -238.19,2179.13 -228.35,2169.29 -161.42,2169.29 -147.64,2155.51 -147.64,2013.78 CON1.24@-192.91,1968.5
GPIO2_B3/I2S0_SDO2: CON1.26 U1.63 | length 5003.7
  Top w3.94: U1.63@-3413.39,1937.01 -3466.54,1937.01 -3513.78,1984.25 -3513.78,2785.43 -3440.94,2858.27 -488.19,2858.27 -472.44,2842.52 -472.44,2732.28 -338.58,2598.43 -291.34,2598.43 -248.03,2555.12 -248.03,2173.23 -232.28,2157.48 -167.32,2157.48 -159.45,2149.61 -159.45,2080.71 CON1.26@-192.91,2047.24
GPIO4_B2/I2S0_SDO3: CON1.28 U1.62 | length 4813.9
  Top w3.94: U1.62@-3413.39,1976.38 -3476.38,1976.38 -3503.94,2003.94 -3503.94,2779.53 -3435.04,2848.43 -494.09,2848.43 -480.31,2834.65 -480.31,2726.38 -342.52,2588.58 -295.28,2588.58 -257.87,2551.18 -257.87,2151.57 -232.28,2125.98 CON1.28@-192.91,2125.98
GPIO4_D6_D: CON1.1 U1.1 | length 2075.8
  Top w3.94: U1.1@-2035.43,874.02 -1996.06,874.02 -1952.76,917.32 -1952.76,1019.68 -1913.39,1059.06 -157.48,1059.06 CON1.1@-114.17,1102.36
HOST1-5V: E1.1 E2.1 J9.1 J9.5 U13.1 | length 979.6
  Top w59.06: J9.5@-4181.89,1275.59 J9.1@-4280.31,1275.59 -4289.37,1284.65 E1.1@-4289.37,1503.94 -4108.27,1503.94 -4009.84,1405.51 E2.1@-3681.1,1405.51
HPOUT_L: J1.27 U1.80 | length 1146.9
  Top w11.81: U1.80@-3413.39,1267.72 v1(-3374.02,1267.72) ; v1(-3094.49,706.69) -3094.49,643.7 -2960.63,509.84 J1.27@-2960.63,440.94
  Power w11.81: v1(-3374.02,1267.72) -3356.3,1250 -3356.3,874.02 -3326.77,844.49 -3139.76,844.49 -3094.49,799.21 v1(-3094.49,706.69)
HPOUT_R: J1.26 U1.81 | length 1095.9
  Top w11.81: U1.81@-3413.39,1228.35 v1(-3374.02,1228.35) ; v1(-3116.14,706.69) -3116.14,633.86 -2980.31,498.03 J1.26@-2980.32,440.94
  Power w11.81: v1(-3374.02,1228.35) -3374.02,868.11 -3330.71,824.8 -3149.61,824.8 -3116.14,791.34 v1(-3116.14,706.69)
HUB_1V8: C72.1 U14.12 U14.28 | length 729.9
  Top w11.81: v1(-2716.54,521.65) -2716.54,564.86 U14.12@-2717.03,565.35 -2717.03,655.01 C72.1@-2696.85,675.2 ; v1(-2517.72,316.93) -2445.28,316.93 -2435.43,326.77 U14.28@-2435.43,368.03
  Bottom w15.75: v1(-2716.54,521.65) -2661.42,521.65 -2624.02,559.06 -2545.56,559.06 -2517.72,531.22 v1(-2517.72,316.93)
HUB_3V3: C73.1 C75.1 R86.2 R88.1 U14.13 U14.21 | length 1258.3
  Top w11.81: C75.1@-2744.09,659.45 -2742.63,657.99 U14.13@-2742.63,565.35 -2742.13,564.85 v1(-2742.13,523.62) ; U14.21@-2614.63,368.03 -2614.63,293.77 C73.1@-2564.96,244.09
  Top w15.75: R86.2@-2694.88,147.64 -2679.13,131.89 -2517.72,131.89 -2509.84,139.76 v1(-2509.84,202.76) R88.1@-2509.84,222.44 -2543.31,222.44 C73.1@-2564.96,244.09
  Bottom w15.75: v1(-2742.13,523.62) -2742.13,539.37 -2734.25,547.24 -2673.23,547.24 -2641.73,578.74 -2537.4,578.74 -2496.06,537.4 -2496.06,216.54 v1(-2509.84,202.76)
I2C0_SCL: R11.1 R75.2 U1.11 | length 3496.7
  Top w3.94: R11.1@-3962.6,2104.33 v1(-3962.6,2120.08) ; v1(-3259.84,1984.25) -3212.6,2031.5 -2080.71,2031.5 -2072.83,2023.62 -2072.83,1273.62 v1(-2066.93,1267.72) U1.11@-2035.43,1267.72 ; R75.2@-1858.27,631.89 v1(-1858.27,761.81)
  Bottom w3.94: v1(-3962.6,2120.08) -3929.13,2086.61 -3362.2,2086.61 v1(-3259.84,1984.25) ; v1(-2066.93,1267.72) -2051.18,1251.97 -2051.18,954.72 v1(-1858.27,761.81)
I2C0_SCL_80398738: CON1.21 U6.36 | length 551.4
  Top w3.94: U6.36@-505.91,2096.46 -450.79,2096.46 -444.88,2102.36 -360.24,2102.36 v1(-301.18,2043.31) ; v1(-301.18,1925.2) -149.61,1925.2 CON1.21@-114.17,1889.76
  Bottom w3.94: v1(-301.18,1925.2) v1(-301.18,2043.31)
I2C0_SDA: R13.1 R76.2 U1.10 | length 3424.1
  Top w3.94: R13.1@-3923.23,2104.33 v1(-3923.23,2120.08) ; v1(-3232.28,1984.25) -3192.91,2023.62 -2094.49,2023.62 -2080.71,2009.84 -2080.71,1238.19 -2070.87,1228.35 v1(-2066.93,1228.35) U1.10@-2035.43,1228.35 ; R76.2@-1897.64,631.89 v1(-1897.64,761.81)
  Bottom w3.94: v1(-3923.23,2120.08) -3899.61,2096.46 -3344.49,2096.46 v1(-3232.28,1984.25) ; v1(-2066.93,1228.35) -2061.02,1222.44 -2061.02,950.79 -1897.64,787.4 v1(-1897.64,761.81)
I2C0_SDA_80398737: CON1.19 U6.37 | length 636.2
  Top w3.94: U6.37@-470.47,2112.2 -354.33,2112.2 -338.58,2096.46 v1(-311.02,2096.46) ; v1(-301.18,1852.36) -277.56,1852.36 -183.07,1852.36 -141.73,1811.02 CON1.19@-114.17,1811.02
  Bottom w3.94: v1(-311.02,2096.46) -279.53,2064.96 -279.53,1874.02 v1(-301.18,1852.36)
I2C1_SCL_80398697: CON1.20 R50.2 U6.39 | length 650.4
  Top w3.94: U6.39@-470.47,2143.7 -452.76,2143.7 -444.88,2135.83 -375.98,2135.83 R50.2@-334.65,2177.17 v1(-334.65,2159.45) ; v1(-283.46,1811.02) CON1.20@-192.91,1811.02
  Bottom w3.94: v1(-334.65,2159.45) -263.78,2088.58 -263.78,1830.71 v1(-283.46,1811.02)
I2C1_SDA_80398695: CON1.17 R49.2 U6.38 | length 793.7
  Top w3.94: U6.38@-505.91,2127.95 -448.82,2127.95 -444.88,2124.02 -368.11,2124.02 -360.24,2131.89 R49.2@-334.65,2131.89 v1(-334.65,2116.14) ; v1(-299.21,1767.72) -149.61,1767.72 CON1.17@-114.17,1732.28
  Bottom w3.94: v1(-334.65,2116.14) -307.09,2116.14 -271.65,2080.71 -271.65,1852.36 -299.21,1824.8 v1(-299.21,1767.72)
I2S0_LRCK_RX: CON1.15 U1.67 | length 5841.9
  Top w3.94: U1.67@-3413.39,1779.53 -3484.25,1779.53 -3576.77,1872.05 -3576.77,2769.68 -3458.66,2887.8 -326.77,2887.8 -305.12,2866.14 -305.12,2738.19 -216.54,2649.61 -84.65,2649.61 -61.02,2625.98 -61.02,1706.69 CON1.15@-114.17,1653.54
I2S0_LRCK_TX: CON1.13 U1.68 | length 5990.2
  Top w3.94: U1.68@-3413.39,1740.16 -3464.57,1740.16 -3586.61,1862.2 -3586.61,2773.62 -3462.6,2897.64 -322.83,2897.64 -297.24,2872.05 -297.24,2742.13 -214.57,2659.45 -80.71,2659.45 -51.18,2629.92 -51.18,1637.79 CON1.13@-114.17,1574.8
I2S0_MCLK: CON1.14 U1.71 | length 6358.5
  Top w3.94: U1.71@-3413.39,1622.05 -3448.82,1622.05 -3474.41,1647.64 -3474.41,1720.47 -3606.3,1852.36 -3606.3,2787.4 -3476.38,2917.32 -314.96,2917.32 -281.5,2883.86 -281.5,2750 -210.63,2679.13 -72.83,2679.13 -31.5,2637.8 -31.5,1584.65 -80.71,1535.43 -185.04,1535.43 -192.91,1543.31 CON1.14@-192.91,1574.8
I2S0_SCLK_RX/PDM_CLK: CON1.18 ED1.1 J6.10 U1.69 | length 5336
  Top w3.94: U1.69@-3413.39,1700.79 -3364.17,1700.79 -3358.27,1706.69 -3358.27,2035.43 -3305.12,2084.65 v1(-2669.29,2084.65) ; v1(-2669.29,2263.78) v1(-2669.29,2511.81) ; v1(-2277.56,2511.81) ED1.1@-2255.91,2511.76 ED1.1@-2255.91,2511.76 J6.10@-2255.91,2594.49 ; v1(-1409.45,2511.81) -925.2,2511.81 v1(-911.42,2525.59) ; v1(-255.91,2635.83) -84.65,2635.83 -70.87,2622.05 -70.87,1722.44 -98.43,1694.88 -155.51,1694.88 CON1.18@-192.91,1732.28
  Bottom w3.94: v1(-2669.29,2084.65) v1(-2669.29,2263.78) ; v1(-2669.29,2511.81) v1(-2277.56,2511.81) v1(-1409.45,2511.81) ; v1(-911.42,2525.59) -911.42,2535.43 -828.74,2618.11 -273.62,2618.11 v1(-255.91,2635.83)
I2S0_SDI0/PDM_SDI0: J6.22 U1.61 | length 2015.8
  Top w3.94: U1.61@-3413.39,2015.75 -3478.35,2015.75 -3494.09,2031.5 -3494.09,2775.59 -3431.1,2838.58 -2641.73,2838.58 -2492.13,2688.98 J6.22@-2492.13,2594.49
I2S0_SDI1/PDM_SDI1: ED2.2 J6.23 U1.60 | length 1890.9
  Top w3.94: U1.60@-3295.28,2133.86 -3295.28,2177.17 -3307.09,2188.98 -3383.86,2188.98 -3464.57,2269.68 -3464.57,2791.34 -3427.17,2828.74 -2917.32,2828.74 -2895.67,2807.09 -2805.95,2807.09 ED2.2@-2786.27,2787.4 -2614.17,2787.4 -2511.81,2685.04 J6.23@-2511.81,2594.49
I2S0_SDI2/PDM_SDI2: ED3.1 J6.24 U1.59 | length 1885.9
  Top w3.94: U1.59@-3255.91,2133.86 -3255.91,2167.32 -3287.4,2198.82 -3379.92,2198.82 -3454.72,2273.62 -3454.72,2787.4 -3423.23,2818.9 -2921.26,2818.9 -2870.08,2767.72 -2805.17,2767.72 ED3.1@-2785.48,2748.03 -2767.76,2765.75 -2614.17,2765.75 -2531.5,2683.07 J6.24@-2531.5,2594.49
I2S0_SDI2/PDM_SDI3: ED4.2 J6.25 U1.58 | length 1880.6
  Top w3.94: U1.58@-3216.54,2133.86 -3216.54,2173.23 -3253.94,2210.63 -3375.98,2210.63 -3444.88,2279.53 -3444.88,2781.5 -3417.32,2809.06 -2927.17,2809.06 -2847.59,2729.48 -2805.12,2729.48 ED4.2@-2786.27,2710.63 -2756.74,2740.16 -2614.17,2740.16 -2551.18,2677.17 J6.25@-2551.18,2594.49
LANWAKEB: R58.1 U7.19 | length 103.1
  Top w11.81: U7.19@-3721.96,662.9 -3721.96,675.2 -3696.37,700.79 R58.1@-3641.73,700.79
LCDC_CLK: FP1.30 U1.17 | length 969.1
  Top w3.94: U1.17@-2035.43,1503.94 v1(-1606.3,1503.94) ; FP1.30@-1606.3,1905.51 -1606.3,1946.85 v1(-1586.61,1966.54)
  Bottom w3.94: v1(-1606.3,1503.94) -1606.3,1946.85 v1(-1586.61,1966.54)
LCDC_D0: FP1.7 U1.21 | length 1093.7
  Top w3.94: U1.21@-2035.43,1661.42 -1208.66,1661.42 -1153.54,1716.54 FP1.7@-1153.54,1905.51
LCDC_D1/I2S1_LRCK_TX_M0: FP1.8 U1.22 | length 1062.6
  Top w3.94: U1.22@-2035.43,1700.79 -2000,1700.79 -1970.47,1671.26 -1251.97,1671.26 -1173.23,1750 FP1.8@-1173.23,1905.51
LCDC_D2: FP1.9 U1.23 | length 1062.6
  Top w3.94: U1.23@-2035.43,1740.16 -2003.94,1740.16 -1998.03,1734.25 -1998.03,1714.57 -1964.57,1681.1 -1261.81,1681.1 -1192.91,1750 FP1.9@-1192.91,1905.51
LCDC_D3/I2S1_SDO0_M0: FP1.10 U1.24 | length 1061.4
  Top w3.94: U1.24@-2035.43,1779.53 -2005.91,1779.53 -1988.19,1761.81 -1988.19,1720.47 -1958.66,1690.94 -1275.59,1690.94 -1212.6,1753.94 FP1.10@-1212.6,1905.51
LCDC_D4: FP1.11 U1.25 | length 1067.2
  Top w3.94: U1.25@-2035.43,1818.9 -2001.97,1818.9 -1978.35,1795.28 -1978.35,1730.31 -1948.82,1700.79 -1279.53,1700.79 -1232.28,1748.03 FP1.11@-1232.28,1905.51
LCDC_D5: FP1.12 U1.27 | length 1085.7
  Top w3.94: U1.27@-2035.43,1897.64 -1996.06,1897.64 -1958.66,1860.24 -1958.66,1744.09 -1935.04,1720.47 -1293.31,1720.47 -1261.81,1751.97 -1261.81,1862.2 -1251.97,1872.05 FP1.12@-1251.97,1905.51
LCDC_D6: FP1.15 U1.26 | length 1139.9
  Top w3.94: U1.26@-2035.43,1858.27 -1996.06,1858.27 -1968.5,1830.71 -1968.5,1736.22 -1942.91,1710.63 -1285.43,1710.63 -1248.03,1748.03 v1(-1248.03,1854.33) ; v1(-1311.02,1854.33) FP1.15@-1311.02,1905.51
  Bottom w3.94: v1(-1311.02,1854.33) v1(-1248.03,1854.33)
LCDC_D7/I2S1_SDI0_M0: FP1.16 U1.28 | length 1035.9
  Top w3.94: U1.28@-2035.43,1937.01 -1996.06,1937.01 -1948.82,1889.76 -1948.82,1750 -1929.13,1730.31 -1350.39,1730.31 -1330.71,1750 FP1.16@-1330.71,1905.51
LCDC_D8/MAC_CLK: FP1.17 U1.29 | length 1027.8
  Top w3.94: U1.29@-2035.43,1976.38 -2001.97,1976.38 -1938.98,1913.39 -1938.98,1755.91 -1923.23,1740.16 -1372.05,1740.16 -1350.39,1761.81 FP1.17@-1350.39,1905.51
LCDC_D9/MAC_MDC: FP1.18 U1.30 | length 1023.2
  Top w3.94: U1.30@-2035.43,2015.75 -2001.97,2015.75 -1929.13,1942.91 -1929.13,1761.81 -1917.32,1750 -1393.7,1750 -1370.08,1773.62 FP1.18@-1370.08,1905.51
LCDC_D10/MAC_MDIO: FP1.19 U1.31 | length 1349.1
  Top w3.94: U1.31@-2153.54,2133.86 -2153.54,2177.17 -2125.98,2204.72 -2003.94,2204.72 -1919.29,2120.08 -1919.29,1767.72 -1911.42,1759.84 -1399.61,1759.84 -1389.76,1769.68 FP1.19@-1389.76,1905.51
LCDC_D11/MAC_RXER: FP1.20 U1.32 | length 1234.7
  Top w3.94: U1.32@-2192.91,2133.86 -2192.91,2187.01 -2165.35,2214.57 -1998.03,2214.57 -1909.45,2125.98 -1909.45,1848.43 -1893.7,1832.68 -1421.26,1832.68 -1409.45,1844.49 FP1.20@-1409.45,1905.51
LCDC_D12/MAC_RXDV: FP1.23 U1.33 | length 1213.2
  Top w3.94: U1.33@-2232.28,2133.86 -2232.28,2187.01 -2194.88,2224.41 -1992.13,2224.41 -1899.61,2131.89 -1899.61,1854.33 -1885.83,1840.55 -1478.35,1840.55 -1468.5,1850.39 FP1.23@-1468.5,1905.51
LCDC_D13/MAC_TXEN: FP1.25 U1.35 | length 1239.9
  Top w3.94: U1.35@-2311.02,2133.86 -2311.02,2177.17 -2244.09,2244.09 -1970.47,2244.09 -1879.92,2153.54 -1879.92,1872.05 -1868.11,1860.24 -1513.78,1860.24 -1507.87,1866.14 FP1.25@-1507.87,1905.51
LCDC_D14/MAC_TXD0: FP1.24 U1.34 | length 1220.2
  Top w3.94: U1.34@-2271.65,2133.86 -2271.65,2181.1 -2218.5,2234.25 -1986.22,2234.25 -1889.76,2137.8 -1889.76,1866.14 -1874.02,1850.39 -1498.03,1850.39 -1488.19,1860.24 FP1.24@-1488.19,1905.51
LCDC_D15/MAC_TXD1: FP1.27 U1.37 | length 1226.8
  Top w3.94: U1.37@-2389.76,2133.86 -2389.76,2169.29 -2295.28,2263.78 -1956.69,2263.78 -1860.24,2167.32 -1860.24,2000 -1854.33,1994.09 v1(-1547.24,1994.09) ; FP1.27@-1547.24,1905.51 v1(-1547.24,1938.98)
  Bottom w3.94: v1(-1547.24,1938.98) -1533.46,1952.76 -1533.46,1980.31 v1(-1547.24,1994.09)
LCDC_D16/MAC_RXD0: FP1.26 U1.36 | length 1173.7
  Top w3.94: U1.36@-2350.39,2133.86 -2350.39,2173.23 -2269.69,2253.94 -1962.6,2253.94 -1870.08,2161.42 -1870.08,1994.09 -1856.3,1980.31 -1541.34,1980.31 -1527.56,1966.54 FP1.26@-1527.56,1905.51
LCDC_D17/MAC_RXD1: FP1.28 U1.38 | length 1259.5
  Top w3.94: U1.38@-2429.13,2133.86 -2429.13,2171.26 -2326.77,2273.62 -1950.79,2273.62 -1850.39,2173.23 -1850.39,2017.72 -1840.55,2007.87 v1(-1570.87,2007.87) ; FP1.28@-1566.93,1905.51 -1566.93,1946.85 v1(-1547.24,1966.54)
  Bottom w3.94: v1(-1570.87,2007.87) -1570.87,1990.16 v1(-1547.24,1966.54)
LCDC_DEN/I2S1_SCLK_TX_M0: FP1.34 U1.20 | length 700.8
  Top w3.94: U1.20@-2035.43,1622.05 v1(-1685.04,1622.05) ; FP1.34@-1685.04,1905.51 v1(-1685.04,1938.98)
  Bottom w3.94: v1(-1685.04,1622.05) v1(-1685.04,1938.98)
LCDC_HSYNC: FP1.32 U1.19 | length 779.5
  Top w3.94: U1.19@-2035.43,1582.68 v1(-1645.67,1582.68) ; FP1.32@-1645.67,1905.51 v1(-1645.67,1938.98)
  Bottom w3.94: v1(-1645.67,1582.68) v1(-1645.67,1938.98)
LCDC_VSYNC: FP1.33 U1.18 | length 859.1
  Top w3.94: U1.18@-2035.43,1543.31 v1(-1685.04,1543.31) ; v1(-1685.04,1966.54) -1665.35,1946.85 FP1.33@-1665.35,1905.51
  Bottom w3.94: v1(-1685.04,1543.31) -1665.35,1562.99 -1665.35,1946.85 v1(-1685.04,1966.54)
LED0: LED1.2 U6.50 | length 197.4
  Top w7.87: U6.50@-505.91,2348.43 -501.97,2348.43 -496.06,2342.52 -452.76,2342.52 -409.45,2385.83 -409.45,2420.08 LED1.2@-376.72,2452.81
LED0/SPICSB: R52.1 R56.1 TP5.1 U7.15 | length 276
  Top w3.94: U7.15@-3692.43,574.32 -3691.95,574.8 v1(-3669.29,574.8) -3663.39,568.9 -3547.44,568.9 -3539.37,576.96 R56.1@-3539.37,661.42
  Bottom w3.94: TP5.1@-3694.88,562.99 TP5.1@-3692.91,564.96 ; TP5.1@-3692.91,566.93 TP5.1@-3692.91,564.96 ; v1(-3669.29,574.8) -3683.07,574.8 TP5.1@-3692.91,564.96
LED1: LED2.2 U6.49 | length 159
  Top w7.87: U6.49@-505.91,2316.93 -501.97,2316.93 -494.09,2324.8 -447.64,2324.8 LED2.2@-378.69,2393.75
LED1/SPISCK: R53.1 R55.1 TP7.1 U7.17 | length 116
  Top w3.94: U7.17@-3692.43,613.69 -3691.95,614.17 v1(-3669.29,614.17) -3651.57,614.17 R53.1@-3641.73,624.02 R55.1@-3641.73,661.42
  Bottom w3.94: TP7.1@-3692.91,614.17 v1(-3669.29,614.17)
LED2: LED3.2 U6.48 | length 105.7
  Top w7.87: U6.48@-470.47,2301.18 -440.94,2301.18 -407.43,2334.7 LED3.2@-378.69,2334.7
LED+: C11.1 D1.2 FP1.2 U4.5 | length 1336.6
  Top w11.81: -1061.02,1950.79 -1055.12,1944.88 FP1.2@-1055.12,1905.51
  Top w15.75: D1.2@-736.22,1530.91 v1(-736.22,1559.06) ; U4.5@-551.18,1318.9 v1(-521.65,1318.9)
  Top w27.56: -1061.02,1950.79 -1061.02,2027.56 -1043.31,2045.28 -911.42,2045.28 -885.83,2019.68 -885.83,1761.81 C11.1@-736.22,1612.2 ; -753.94,1651.57 -736.22,1633.86 C11.1@-736.22,1612.2 ; C11.1@-736.22,1596.46 C11.1@-736.22,1612.2
  Bottom w15.75: v1(-736.22,1559.06) -564.96,1559.06 -521.65,1515.75 v1(-521.65,1318.9)
LED-: FP1.1 R15.2 R20.1 | length 849.3
  Top w15.75: R20.1@-1007.87,1988.19 -1005.91,1986.22 -1005.91,1962.6 -1033.46,1935.04 -1033.46,1755.91 -1007.87,1730.31 -925.2,1730.31 -868.11,1673.23 -868.11,1446.85 -750,1328.74 R15.2@-750,1316.93
LINEOUT_L: J1.29 U1.79 | length 1342.9
  Top w11.81: U1.79@-3413.39,1307.09 v1(-3377.95,1307.09) ; v1(-3037.4,706.69) -3037.4,643.7 -2881.89,488.19 -2881.89,399.61 -2885.83,395.67 -2913.39,395.67 -2921.26,403.54 J1.29@-2921.26,440.94
  Bottom w11.81: v1(-3377.95,1307.09) -3383.86,1307.09 -3391.73,1299.21 -3391.73,909.45 -3230.31,748.03 -3062.99,748.03 -3037.4,722.44 v1(-3037.4,706.69)
LINEOUT_R: J1.30 U1.78 | length 1260.7
  Top w11.81: U1.78@-3413.39,1346.46 v1(-3377.95,1346.46) ; v1(-3061.02,706.69) -3061.02,639.76 -2901.57,480.31 J1.30@-2901.57,440.94
  Bottom w11.81: v1(-3377.95,1346.46) -3393.7,1346.46 -3407.48,1332.68 -3407.48,901.57 -3234.25,728.35 -3082.68,728.35 v1(-3061.02,706.69)
M_DM1: U1.109 U14.15 | length 815.7
  Top w5.91: U14.15@-2768.23,368.03 -2768.23,396.53 -2760.35,404.41 -2760.35,429.68 -2739.7,450.33 -2463.06,450.33 v1(-2458.66,454.72) ; U1.109@-2586.61,755.91 -2586.61,724.41 -2571.85,709.65 -2571.85,654.53 v1(-2576.77,649.61)
  Bottom w5.91: v1(-2576.77,649.61) -2571.85,644.68 -2571.85,627.95 -2560.04,616.14 -2488.33,616.14 -2433.07,560.88 -2433.07,457.82 -2441.08,449.8 -2453.74,449.8 v1(-2458.66,454.72)
M_DP1: U1.110 U14.16 | length 816.1
  Top w5.91: U14.16@-2742.63,368.03 -2742.63,396.53 -2750.51,404.41 -2750.51,425.6 -2735.62,440.49 -2464.11,440.49 v1(-2458.66,435.04) ; v1(-2557.09,649.61) -2562.01,654.53 -2562.01,709.65 -2547.24,724.41 U1.110@-2547.24,755.91
  Bottom w5.91: v1(-2557.09,649.61) -2562.01,644.68 -2562.01,632.03 -2555.96,625.98 -2507.87,625.98 -2484.25,625.98 -2423.23,564.96 -2423.23,453.74 -2437.01,439.96 -2453.74,439.96 v1(-2458.66,435.04)
MASKROM: SW3.2 U1.43 | length 1673.7
  Top w3.94: v1(-2740.16,2592.52) -2740.16,2257.87 -2728.35,2246.06 -2677.17,2246.06 -2625.98,2194.88 U1.43@-2625.98,2133.86 ; SW3.2@-1746.06,2448.82 v1(-1746.06,2592.52)
  Bottom w3.94: v1(-2740.16,2592.52) v1(-1746.06,2592.52)
MDI0+: JP1.1 U7.2 | length 356.8
  Top w3.94: v1(-3874.02,614.17) -3850.39,614.17 U7.2@-3849.91,613.69
  Bottom w3.94: JP1.1@-4155.65,617.83 -4123.25,585.44 -4118.94,585.44 -4109.58,594.8 -4109.58,610.55 -4092.18,627.95 -3974.41,627.95 -3954.72,608.27 -3879.92,608.27 v1(-3874.02,614.17)
MDI0-: JP1.2 U7.3 | length 337.6
  Top w3.94: v1(-3874.02,594.49) -3850.4,594.49 U7.3@-3849.91,594
  Bottom w3.94: JP1.2@-4055.65,567.83 -4078.96,591.15 -4098.05,591.15 -4101.71,594.8 -4101.71,607.29 -4088.92,620.08 -3978.35,620.08 -3958.66,600.39 -3879.92,600.39 v1(-3874.02,594.49)
MICBIAS1: J1.1 U1.76 | length 1253.5
  Top w11.81: v1(-3472.44,405.51) J1.1@-3472.44,440.94
  Top w15.75: v1(-3448.82,1425.2) U1.76@-3413.39,1425.2
  Bottom w15.75: v1(-3472.44,405.51) -3472.44,537.4 -3570.87,635.83 -3570.87,675.2 -3590.55,694.88 -3590.55,1377.95 -3543.31,1425.2 v1(-3448.82,1425.2)
MICBIAS2: J1.21 U1.77 | length 1139.4
  Top w11.81: v1(-3228.35,706.69) -3228.35,643.7 -3078.74,494.09 J1.21@-3078.74,440.94
  Top w15.75: v1(-3448.82,1385.83) U1.77@-3413.39,1385.83
  Bottom w11.81: v1(-3448.82,1385.83) -3427.17,1364.17 -3427.17,895.67 -3238.19,706.69 v1(-3228.35,706.69)
MICN4: J1.8 U1.83 | length 957.6
  Top w3.94: v1(-3553.15,734.25) -3547.24,740.16 -3547.24,1059.06 -3472.44,1133.86 -3442.91,1133.86 -3427.17,1149.61 U1.83@-3413.39,1149.61 ; J1.8@-3334.65,440.94 v1(-3334.65,474.41)
  Bottom w3.94: v1(-3553.15,734.25) -3547.24,728.35 -3547.24,651.91 -3393.7,498.37 -3393.7,458.66 -3379.92,444.88 -3352.36,444.88 -3340.55,456.69 -3340.55,468.5 v1(-3334.65,474.41)
MICN5: J1.10 U1.85 | length 850.3
  Top w3.94: v1(-3525.59,787.4) -3519.69,793.31 -3519.69,1035.1 -3499.66,1055.12 -3442.91,1055.12 -3427.17,1070.87 U1.85@-3413.39,1070.87 ; J1.10@-3295.28,440.94 v1(-3295.28,474.41)
  Bottom w3.94: v1(-3525.59,787.4) -3519.68,781.5 -3519.68,669.97 -3349.72,500 -3294.6,500 -3289.37,494.77 -3289.37,480.31 v1(-3295.28,474.41)
MICN6: J1.14 U1.87 | length 841.1
  Top w3.94: v1(-3498.03,755.91) -3492.13,761.81 -3492.13,954.39 -3470.13,976.38 -3442.91,976.38 -3427.17,992.13 U1.87@-3413.39,992.13 ; J1.14@-3216.54,440.94 v1(-3216.54,474.41)
  Bottom w3.94: v1(-3498.03,755.91) -3492.13,750 -3492.13,683.75 -3335.94,527.56 -3274.92,527.56 -3259.84,512.49 -3259.84,448.82 -3251.97,440.94 -3232.28,440.94 -3222.44,450.79 -3222.44,468.5 v1(-3216.54,474.41)
MICN7: J1.16 U1.89 | length 694.6
  Top w3.94: v1(-3470.47,787.4) -3464.57,793.31 -3464.57,887.8 -3454.72,897.64 -3442.91,897.64 -3427.17,913.39 U1.89@-3413.39,913.39 ; J1.16@-3177.17,440.94 v1(-3177.17,474.41)
  Bottom w3.94: v1(-3470.47,787.4) -3464.57,781.5 -3464.57,696.37 -3325.28,557.09 -3227.67,557.09 -3171.26,500.68 -3171.26,480.31 v1(-3177.17,474.41)
MICN8: J1.20 U1.91 | length 504.5
  Top w3.94: U1.91@-3295.28,755.91 -3295.28,742.13 -3279.53,726.38 -3279.53,600.39 -3263.78,584.65 -3246.06,584.65 v1(-3240.16,578.74) ; J1.20@-3098.43,440.94 v1(-3098.43,474.41)
  Bottom w3.94: v1(-3240.16,578.74) -3234.25,584.65 -3206.35,584.65 -3141.73,520.02 -3141.73,454.72 -3131.89,444.88 -3114.17,444.88 -3104.33,454.72 -3104.33,468.5 v1(-3098.43,474.41)
MICP4: J1.7 U1.84 | length 918.1
  Top w3.94: v1(-3533.46,734.25) -3539.37,740.16 -3539.37,1055.12 -3468.5,1125.98 -3442.91,1125.98 -3427.17,1110.24 U1.84@-3413.39,1110.24 ; J1.7@-3354.33,440.94 v1(-3354.33,474.41)
  Bottom w3.94: v1(-3533.46,734.25) -3539.37,728.35 -3539.37,655.17 -3385.83,501.63 -3385.83,461.92 -3376.66,452.76 -3355.62,452.76 -3348.43,459.95 -3348.43,468.5 v1(-3354.33,474.41)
